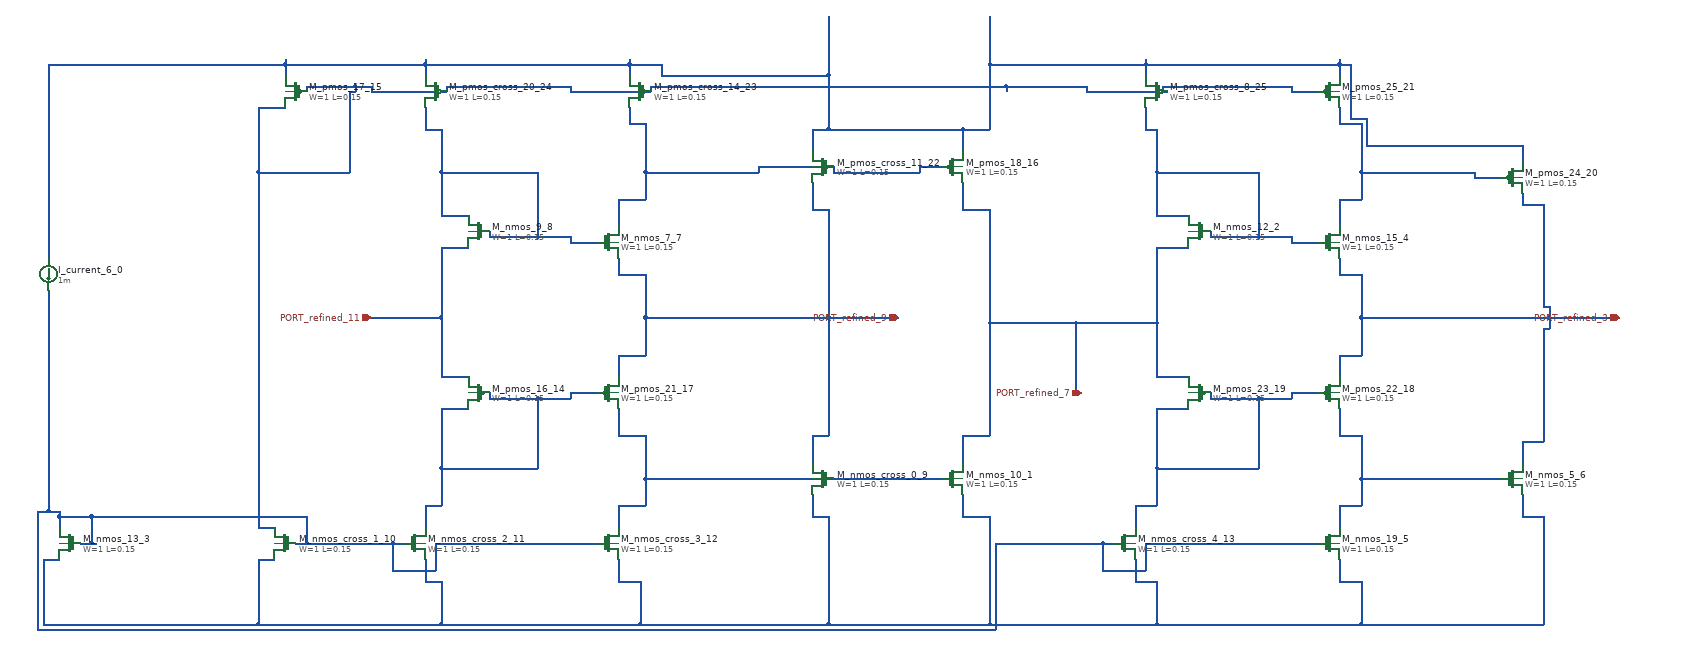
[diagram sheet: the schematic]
v {xschem version=3.4.8 file_version=1.2}
G {}
K {}
V {}
S {}
E {}
C {devices/isource.sym} 120 500 0 0 {name="I_current_6_0" value=1m}
C {sky130_fd_pr/nfet3_01v8.sym} 1800 880 0 0 {name="M_nmos_10_1"
W=1
L=0.15
body=GND
nf=1
mult=1
ad="expr('int((@nf + 1)/2) * @W / @nf * 0.29')"
pd="expr('2*int((@nf + 1)/2) * (@W / @nf + 0.29)')"
as="expr('int((@nf + 2)/2) * @W / @nf * 0.29')"
ps="expr('2*int((@nf + 2)/2) * (@W / @nf + 0.29)')"
nrd="expr('0.29 / @W ')" nrs="expr('0.29 / @W ')"
sa=0 sb=0 sd=0
model=nfet_01v8
spiceprefix=X
}
C {sky130_fd_pr/nfet3_01v8.sym} 2260 420 0 1 {name="M_nmos_12_2"
W=1
L=0.15
body=GND
nf=1
mult=1
ad="expr('int((@nf + 1)/2) * @W / @nf * 0.29')"
pd="expr('2*int((@nf + 1)/2) * (@W / @nf + 0.29)')"
as="expr('int((@nf + 2)/2) * @W / @nf * 0.29')"
ps="expr('2*int((@nf + 2)/2) * (@W / @nf + 0.29)')"
nrd="expr('0.29 / @W ')" nrs="expr('0.29 / @W ')"
sa=0 sb=0 sd=0
model=nfet_01v8
spiceprefix=X
}
C {sky130_fd_pr/nfet3_01v8.sym} 160 1000 0 1 {name="M_nmos_13_3"
W=1
L=0.15
body=GND
nf=1
mult=1
ad="expr('int((@nf + 1)/2) * @W / @nf * 0.29')"
pd="expr('2*int((@nf + 1)/2) * (@W / @nf + 0.29)')"
as="expr('int((@nf + 2)/2) * @W / @nf * 0.29')"
ps="expr('2*int((@nf + 2)/2) * (@W / @nf + 0.29)')"
nrd="expr('0.29 / @W ')" nrs="expr('0.29 / @W ')"
sa=0 sb=0 sd=0
model=nfet_01v8
spiceprefix=X
}
C {sky130_fd_pr/nfet3_01v8.sym} 2500 440 0 0 {name="M_nmos_15_4"
W=1
L=0.15
body=GND
nf=1
mult=1
ad="expr('int((@nf + 1)/2) * @W / @nf * 0.29')"
pd="expr('2*int((@nf + 1)/2) * (@W / @nf + 0.29)')"
as="expr('int((@nf + 2)/2) * @W / @nf * 0.29')"
ps="expr('2*int((@nf + 2)/2) * (@W / @nf + 0.29)')"
nrd="expr('0.29 / @W ')" nrs="expr('0.29 / @W ')"
sa=0 sb=0 sd=0
model=nfet_01v8
spiceprefix=X
}
C {sky130_fd_pr/nfet3_01v8.sym} 2500 1000 0 0 {name="M_nmos_19_5"
W=1
L=0.15
body=GND
nf=1
mult=1
ad="expr('int((@nf + 1)/2) * @W / @nf * 0.29')"
pd="expr('2*int((@nf + 1)/2) * (@W / @nf + 0.29)')"
as="expr('int((@nf + 2)/2) * @W / @nf * 0.29')"
ps="expr('2*int((@nf + 2)/2) * (@W / @nf + 0.29)')"
nrd="expr('0.29 / @W ')" nrs="expr('0.29 / @W ')"
sa=0 sb=0 sd=0
model=nfet_01v8
spiceprefix=X
}
C {sky130_fd_pr/nfet3_01v8.sym} 2840 880 0 0 {name="M_nmos_5_6"
W=1
L=0.15
body=GND
nf=1
mult=1
ad="expr('int((@nf + 1)/2) * @W / @nf * 0.29')"
pd="expr('2*int((@nf + 1)/2) * (@W / @nf + 0.29)')"
as="expr('int((@nf + 2)/2) * @W / @nf * 0.29')"
ps="expr('2*int((@nf + 2)/2) * (@W / @nf + 0.29)')"
nrd="expr('0.29 / @W ')" nrs="expr('0.29 / @W ')"
sa=0 sb=0 sd=0
model=nfet_01v8
spiceprefix=X
}
C {sky130_fd_pr/nfet3_01v8.sym} 1160 440 0 0 {name="M_nmos_7_7"
W=1
L=0.15
body=GND
nf=1
mult=1
ad="expr('int((@nf + 1)/2) * @W / @nf * 0.29')"
pd="expr('2*int((@nf + 1)/2) * (@W / @nf + 0.29)')"
as="expr('int((@nf + 2)/2) * @W / @nf * 0.29')"
ps="expr('2*int((@nf + 2)/2) * (@W / @nf + 0.29)')"
nrd="expr('0.29 / @W ')" nrs="expr('0.29 / @W ')"
sa=0 sb=0 sd=0
model=nfet_01v8
spiceprefix=X
}
C {sky130_fd_pr/nfet3_01v8.sym} 920 420 0 1 {name="M_nmos_9_8"
W=1
L=0.15
body=GND
nf=1
mult=1
ad="expr('int((@nf + 1)/2) * @W / @nf * 0.29')"
pd="expr('2*int((@nf + 1)/2) * (@W / @nf + 0.29)')"
as="expr('int((@nf + 2)/2) * @W / @nf * 0.29')"
ps="expr('2*int((@nf + 2)/2) * (@W / @nf + 0.29)')"
nrd="expr('0.29 / @W ')" nrs="expr('0.29 / @W ')"
sa=0 sb=0 sd=0
model=nfet_01v8
spiceprefix=X
}
C {sky130_fd_pr/nfet3_01v8.sym} 1560 880 0 1 {name="M_nmos_cross_0_9"
W=1
L=0.15
body=GND
nf=1
mult=1
ad="expr('int((@nf + 1)/2) * @W / @nf * 0.29')"
pd="expr('2*int((@nf + 1)/2) * (@W / @nf + 0.29)')"
as="expr('int((@nf + 2)/2) * @W / @nf * 0.29')"
ps="expr('2*int((@nf + 2)/2) * (@W / @nf + 0.29)')"
nrd="expr('0.29 / @W ')" nrs="expr('0.29 / @W ')"
sa=0 sb=0 sd=0
model=nfet_01v8
spiceprefix=X
}
C {sky130_fd_pr/nfet3_01v8.sym} 560 1000 0 1 {name="M_nmos_cross_1_10"
W=1
L=0.15
body=GND
nf=1
mult=1
ad="expr('int((@nf + 1)/2) * @W / @nf * 0.29')"
pd="expr('2*int((@nf + 1)/2) * (@W / @nf + 0.29)')"
as="expr('int((@nf + 2)/2) * @W / @nf * 0.29')"
ps="expr('2*int((@nf + 2)/2) * (@W / @nf + 0.29)')"
nrd="expr('0.29 / @W ')" nrs="expr('0.29 / @W ')"
sa=0 sb=0 sd=0
model=nfet_01v8
spiceprefix=X
}
C {sky130_fd_pr/nfet3_01v8.sym} 800 1000 0 0 {name="M_nmos_cross_2_11"
W=1
L=0.15
body=GND
nf=1
mult=1
ad="expr('int((@nf + 1)/2) * @W / @nf * 0.29')"
pd="expr('2*int((@nf + 1)/2) * (@W / @nf + 0.29)')"
as="expr('int((@nf + 2)/2) * @W / @nf * 0.29')"
ps="expr('2*int((@nf + 2)/2) * (@W / @nf + 0.29)')"
nrd="expr('0.29 / @W ')" nrs="expr('0.29 / @W ')"
sa=0 sb=0 sd=0
model=nfet_01v8
spiceprefix=X
}
C {sky130_fd_pr/nfet3_01v8.sym} 1160 1000 0 0 {name="M_nmos_cross_3_12"
W=1
L=0.15
body=GND
nf=1
mult=1
ad="expr('int((@nf + 1)/2) * @W / @nf * 0.29')"
pd="expr('2*int((@nf + 1)/2) * (@W / @nf + 0.29)')"
as="expr('int((@nf + 2)/2) * @W / @nf * 0.29')"
ps="expr('2*int((@nf + 2)/2) * (@W / @nf + 0.29)')"
nrd="expr('0.29 / @W ')" nrs="expr('0.29 / @W ')"
sa=0 sb=0 sd=0
model=nfet_01v8
spiceprefix=X
}
C {sky130_fd_pr/nfet3_01v8.sym} 2120 1000 0 0 {name="M_nmos_cross_4_13"
W=1
L=0.15
body=GND
nf=1
mult=1
ad="expr('int((@nf + 1)/2) * @W / @nf * 0.29')"
pd="expr('2*int((@nf + 1)/2) * (@W / @nf + 0.29)')"
as="expr('int((@nf + 2)/2) * @W / @nf * 0.29')"
ps="expr('2*int((@nf + 2)/2) * (@W / @nf + 0.29)')"
nrd="expr('0.29 / @W ')" nrs="expr('0.29 / @W ')"
sa=0 sb=0 sd=0
model=nfet_01v8
spiceprefix=X
}
C {sky130_fd_pr/pfet3_01v8.sym} 920 720 0 1 {name="M_pmos_16_14"
W=1
L=0.15
body=VDD
nf=1
mult=1
ad="expr('int((@nf + 1)/2) * @W / @nf * 0.29')"
pd="expr('2*int((@nf + 1)/2) * (@W / @nf + 0.29)')"
as="expr('int((@nf + 2)/2) * @W / @nf * 0.29')"
ps="expr('2*int((@nf + 2)/2) * (@W / @nf + 0.29)')"
nrd="expr('0.29 / @W ')" nrs="expr('0.29 / @W ')"
sa=0 sb=0 sd=0
model=pfet_01v8
spiceprefix=X
}
C {sky130_fd_pr/pfet3_01v8.sym} 580 160 0 1 {name="M_pmos_17_15"
W=1
L=0.15
body=VDD
nf=1
mult=1
ad="expr('int((@nf + 1)/2) * @W / @nf * 0.29')"
pd="expr('2*int((@nf + 1)/2) * (@W / @nf + 0.29)')"
as="expr('int((@nf + 2)/2) * @W / @nf * 0.29')"
ps="expr('2*int((@nf + 2)/2) * (@W / @nf + 0.29)')"
nrd="expr('0.29 / @W ')" nrs="expr('0.29 / @W ')"
sa=0 sb=0 sd=0
model=pfet_01v8
spiceprefix=X
}
C {sky130_fd_pr/pfet3_01v8.sym} 1800 300 0 0 {name="M_pmos_18_16"
W=1
L=0.15
body=VDD
nf=1
mult=1
ad="expr('int((@nf + 1)/2) * @W / @nf * 0.29')"
pd="expr('2*int((@nf + 1)/2) * (@W / @nf + 0.29)')"
as="expr('int((@nf + 2)/2) * @W / @nf * 0.29')"
ps="expr('2*int((@nf + 2)/2) * (@W / @nf + 0.29)')"
nrd="expr('0.29 / @W ')" nrs="expr('0.29 / @W ')"
sa=0 sb=0 sd=0
model=pfet_01v8
spiceprefix=X
}
C {sky130_fd_pr/pfet3_01v8.sym} 1160 720 0 0 {name="M_pmos_21_17"
W=1
L=0.15
body=VDD
nf=1
mult=1
ad="expr('int((@nf + 1)/2) * @W / @nf * 0.29')"
pd="expr('2*int((@nf + 1)/2) * (@W / @nf + 0.29)')"
as="expr('int((@nf + 2)/2) * @W / @nf * 0.29')"
ps="expr('2*int((@nf + 2)/2) * (@W / @nf + 0.29)')"
nrd="expr('0.29 / @W ')" nrs="expr('0.29 / @W ')"
sa=0 sb=0 sd=0
model=pfet_01v8
spiceprefix=X
}
C {sky130_fd_pr/pfet3_01v8.sym} 2500 720 0 0 {name="M_pmos_22_18"
W=1
L=0.15
body=VDD
nf=1
mult=1
ad="expr('int((@nf + 1)/2) * @W / @nf * 0.29')"
pd="expr('2*int((@nf + 1)/2) * (@W / @nf + 0.29)')"
as="expr('int((@nf + 2)/2) * @W / @nf * 0.29')"
ps="expr('2*int((@nf + 2)/2) * (@W / @nf + 0.29)')"
nrd="expr('0.29 / @W ')" nrs="expr('0.29 / @W ')"
sa=0 sb=0 sd=0
model=pfet_01v8
spiceprefix=X
}
C {sky130_fd_pr/pfet3_01v8.sym} 2260 720 0 1 {name="M_pmos_23_19"
W=1
L=0.15
body=VDD
nf=1
mult=1
ad="expr('int((@nf + 1)/2) * @W / @nf * 0.29')"
pd="expr('2*int((@nf + 1)/2) * (@W / @nf + 0.29)')"
as="expr('int((@nf + 2)/2) * @W / @nf * 0.29')"
ps="expr('2*int((@nf + 2)/2) * (@W / @nf + 0.29)')"
nrd="expr('0.29 / @W ')" nrs="expr('0.29 / @W ')"
sa=0 sb=0 sd=0
model=pfet_01v8
spiceprefix=X
}
C {sky130_fd_pr/pfet3_01v8.sym} 2840 320 0 0 {name="M_pmos_24_20"
W=1
L=0.15
body=VDD
nf=1
mult=1
ad="expr('int((@nf + 1)/2) * @W / @nf * 0.29')"
pd="expr('2*int((@nf + 1)/2) * (@W / @nf + 0.29)')"
as="expr('int((@nf + 2)/2) * @W / @nf * 0.29')"
ps="expr('2*int((@nf + 2)/2) * (@W / @nf + 0.29)')"
nrd="expr('0.29 / @W ')" nrs="expr('0.29 / @W ')"
sa=0 sb=0 sd=0
model=pfet_01v8
spiceprefix=X
}
C {sky130_fd_pr/pfet3_01v8.sym} 2500 160 0 0 {name="M_pmos_25_21"
W=1
L=0.15
body=VDD
nf=1
mult=1
ad="expr('int((@nf + 1)/2) * @W / @nf * 0.29')"
pd="expr('2*int((@nf + 1)/2) * (@W / @nf + 0.29)')"
as="expr('int((@nf + 2)/2) * @W / @nf * 0.29')"
ps="expr('2*int((@nf + 2)/2) * (@W / @nf + 0.29)')"
nrd="expr('0.29 / @W ')" nrs="expr('0.29 / @W ')"
sa=0 sb=0 sd=0
model=pfet_01v8
spiceprefix=X
}
C {sky130_fd_pr/pfet3_01v8.sym} 1560 300 0 1 {name="M_pmos_cross_11_22"
W=1
L=0.15
body=VDD
nf=1
mult=1
ad="expr('int((@nf + 1)/2) * @W / @nf * 0.29')"
pd="expr('2*int((@nf + 1)/2) * (@W / @nf + 0.29)')"
as="expr('int((@nf + 2)/2) * @W / @nf * 0.29')"
ps="expr('2*int((@nf + 2)/2) * (@W / @nf + 0.29)')"
nrd="expr('0.29 / @W ')" nrs="expr('0.29 / @W ')"
sa=0 sb=0 sd=0
model=pfet_01v8
spiceprefix=X
}
C {sky130_fd_pr/pfet3_01v8.sym} 1220 160 0 1 {name="M_pmos_cross_14_23"
W=1
L=0.15
body=VDD
nf=1
mult=1
ad="expr('int((@nf + 1)/2) * @W / @nf * 0.29')"
pd="expr('2*int((@nf + 1)/2) * (@W / @nf + 0.29)')"
as="expr('int((@nf + 2)/2) * @W / @nf * 0.29')"
ps="expr('2*int((@nf + 2)/2) * (@W / @nf + 0.29)')"
nrd="expr('0.29 / @W ')" nrs="expr('0.29 / @W ')"
sa=0 sb=0 sd=0
model=pfet_01v8
spiceprefix=X
}
C {sky130_fd_pr/pfet3_01v8.sym} 840 160 0 1 {name="M_pmos_cross_20_24"
W=1
L=0.15
body=VDD
nf=1
mult=1
ad="expr('int((@nf + 1)/2) * @W / @nf * 0.29')"
pd="expr('2*int((@nf + 1)/2) * (@W / @nf + 0.29)')"
as="expr('int((@nf + 2)/2) * @W / @nf * 0.29')"
ps="expr('2*int((@nf + 2)/2) * (@W / @nf + 0.29)')"
nrd="expr('0.29 / @W ')" nrs="expr('0.29 / @W ')"
sa=0 sb=0 sd=0
model=pfet_01v8
spiceprefix=X
}
C {sky130_fd_pr/pfet3_01v8.sym} 2180 160 0 1 {name="M_pmos_cross_8_25"
W=1
L=0.15
body=VDD
nf=1
mult=1
ad="expr('int((@nf + 1)/2) * @W / @nf * 0.29')"
pd="expr('2*int((@nf + 1)/2) * (@W / @nf + 0.29)')"
as="expr('int((@nf + 2)/2) * @W / @nf * 0.29')"
ps="expr('2*int((@nf + 2)/2) * (@W / @nf + 0.29)')"
nrd="expr('0.29 / @W ')" nrs="expr('0.29 / @W ')"
sa=0 sb=0 sd=0
model=pfet_01v8
spiceprefix=X
}
C {devices/ipin.sym} 3040 580 0 0 {name="p_port_27_26" lab="PORT_refined_3"}
C {devices/ipin.sym} 720 580 0 0 {name="p_port_31_27" lab="PORT_refined_11"}
C {devices/ipin.sym} 1700 580 0 0 {name="p_port_32_28" lab="PORT_refined_9"}
C {devices/ipin.sym} 2040 720 0 0 {name="p_port_33_29" lab="PORT_refined_7"}
N 100 1160 1880 1160 {}
N 760 1050 840 1050 {}
N 2080 1050 2160 1050 {}
N 180 1000 200 1000 {}
N 200 1000 210 1000 {}
N 580 1000 600 1000 {}
N 600 1000 760 1000 {}
N 760 1000 780 1000 {}
N 840 1000 1140 1000 {}
N 1880 1000 2080 1000 {}
N 2080 1000 2100 1000 {}
N 2160 1000 2480 1000 {}
N 140 950 200 950 {}
N 200 950 600 950 {}
N 100 940 120 940 {}
N 120 940 140 940 {}
N 100 1160 100 940 {}
N 120 940 120 530 {}
N 140 970 140 950 {}
N 140 950 140 940 {}
N 200 1000 200 950 {}
N 600 1000 600 950 {}
N 760 1050 760 1000 {}
N 840 1050 840 1000 {}
N 1880 1160 1880 1000 {}
N 2080 1050 2080 1000 {}
N 2160 1050 2160 1000 {}
N 2570 260 2860 260 {}
N 1540 230 1570 230 {}
N 1570 230 1820 230 {}
N 1820 230 1870 230 {}
N 2540 210 2570 210 {}
N 1260 130 1570 130 {}
N 120 110 560 110 {}
N 560 110 820 110 {}
N 820 110 1200 110 {}
N 1200 110 1260 110 {}
N 1870 110 2160 110 {}
N 2160 110 2520 110 {}
N 2520 110 2540 110 {}
N 120 470 120 110 {}
N 560 130 560 110 {}
N 560 110 560 100 {}
N 820 130 820 110 {}
N 820 110 820 100 {}
N 1200 130 1200 110 {}
N 1200 110 1200 100 {}
N 1260 130 1260 110 {}
N 1540 270 1540 230 {}
N 1570 230 1570 130 {}
N 1570 130 1570 20 {}
N 1820 270 1820 230 {}
N 1870 230 1870 110 {}
N 1870 110 1870 20 {}
N 2160 130 2160 110 {}
N 2160 110 2160 100 {}
N 2520 130 2520 110 {}
N 2520 110 2520 100 {}
N 2540 210 2540 110 {}
N 2570 260 2570 210 {}
N 2860 290 2860 260 {}
N 1090 440 1140 440 {}
N 940 430 1030 430 {}
N 1030 430 1090 430 {}
N 850 390 900 390 {}
N 850 310 1030 310 {}
N 820 230 850 230 {}
N 820 230 820 190 {}
N 850 390 850 310 {}
N 850 310 850 230 {}
N 940 430 940 420 {}
N 1030 430 1030 310 {}
N 1090 440 1090 430 {}
N 850 690 900 690 {}
N 720 580 850 580 {}
N 850 450 900 450 {}
N 850 690 850 580 {}
N 850 580 850 450 {}
N 1180 930 1230 930 {}
N 1230 880 1580 880 {}
N 1580 880 1780 880 {}
N 1180 800 1230 800 {}
N 1180 970 1180 930 {}
N 1180 800 1180 750 {}
N 1230 930 1230 880 {}
N 1230 880 1230 800 {}
N 510 970 540 970 {}
N 510 310 680 310 {}
N 510 190 560 190 {}
N 680 160 690 160 {}
N 720 160 860 160 {}
N 1090 160 1240 160 {}
N 2050 160 2190 160 {}
N 2190 160 2200 160 {}
N 2430 160 2480 160 {}
N 600 150 690 150 {}
N 690 150 720 150 {}
N 860 150 1090 150 {}
N 1240 150 1900 150 {}
N 1900 150 2050 150 {}
N 2190 150 2430 150 {}
N 510 970 510 310 {}
N 510 310 510 190 {}
N 600 160 600 150 {}
N 680 310 680 160 {}
N 690 160 690 150 {}
N 720 160 720 150 {}
N 860 160 860 150 {}
N 1090 160 1090 150 {}
N 1240 160 1240 150 {}
N 1900 160 1900 150 {}
N 2050 160 2050 150 {}
N 2190 160 2190 150 {}
N 2430 160 2430 150 {}
N 820 930 850 930 {}
N 850 860 1030 860 {}
N 850 750 900 750 {}
N 940 730 1030 730 {}
N 1030 730 1090 730 {}
N 1090 720 1140 720 {}
N 820 970 820 930 {}
N 850 930 850 860 {}
N 850 860 850 750 {}
N 940 730 940 720 {}
N 1030 860 1030 730 {}
N 1090 730 1090 720 {}
N 2140 930 2180 930 {}
N 2180 860 2370 860 {}
N 2180 750 2240 750 {}
N 2280 730 2370 730 {}
N 2370 730 2430 730 {}
N 2430 720 2480 720 {}
N 2140 970 2140 930 {}
N 2180 930 2180 860 {}
N 2180 860 2180 750 {}
N 2280 730 2280 720 {}
N 2370 860 2370 730 {}
N 2430 730 2430 720 {}
N 2520 360 2560 360 {}
N 2770 320 2820 320 {}
N 2560 310 2770 310 {}
N 2520 220 2560 220 {}
N 2520 410 2520 360 {}
N 2520 220 2520 190 {}
N 2560 360 2560 310 {}
N 2560 310 2560 220 {}
N 2770 320 2770 310 {}
N 2860 810 2900 810 {}
N 2520 650 2560 650 {}
N 2900 600 2910 600 {}
N 2560 580 2910 580 {}
N 2910 580 3040 580 {}
N 2900 560 2910 560 {}
N 2520 500 2560 500 {}
N 2860 370 2900 370 {}
N 2520 690 2520 650 {}
N 2520 500 2520 470 {}
N 2560 650 2560 580 {}
N 2560 580 2560 500 {}
N 2860 850 2860 810 {}
N 2860 370 2860 350 {}
N 2900 810 2900 600 {}
N 2900 560 2900 370 {}
N 2910 600 2910 580 {}
N 2910 580 2910 560 {}
N 2430 440 2480 440 {}
N 2280 430 2370 430 {}
N 2370 430 2430 430 {}
N 2180 390 2240 390 {}
N 2180 310 2370 310 {}
N 2160 230 2180 230 {}
N 2160 230 2160 190 {}
N 2180 390 2180 310 {}
N 2180 310 2180 230 {}
N 2280 430 2280 420 {}
N 2370 430 2370 310 {}
N 2430 440 2430 430 {}
N 2520 930 2560 930 {}
N 2560 880 2820 880 {}
N 2520 800 2560 800 {}
N 2520 970 2520 930 {}
N 2520 800 2520 750 {}
N 2560 930 2560 880 {}
N 2560 880 2560 800 {}
N 110 1150 510 1150 {}
N 510 1150 850 1150 {}
N 850 1150 1220 1150 {}
N 1220 1150 1570 1150 {}
N 1570 1150 1870 1150 {}
N 1870 1150 2180 1150 {}
N 2180 1150 2560 1150 {}
N 2560 1150 2900 1150 {}
N 820 1070 850 1070 {}
N 1180 1070 1220 1070 {}
N 2140 1070 2180 1070 {}
N 2520 1070 2560 1070 {}
N 110 1030 140 1030 {}
N 510 1030 540 1030 {}
N 1540 950 1570 950 {}
N 1820 950 1870 950 {}
N 2860 950 2900 950 {}
N 110 1150 110 1030 {}
N 510 1150 510 1030 {}
N 820 1070 820 1030 {}
N 850 1150 850 1070 {}
N 1180 1070 1180 1030 {}
N 1220 1150 1220 1070 {}
N 1540 950 1540 910 {}
N 1570 1150 1570 950 {}
N 1820 950 1820 910 {}
N 1870 1150 1870 950 {}
N 2140 1070 2140 1030 {}
N 2180 1150 2180 1070 {}
N 2520 1070 2520 1030 {}
N 2560 1150 2560 1070 {}
N 2860 950 2860 910 {}
N 2900 1150 2900 950 {}
N 1820 800 1870 800 {}
N 2030 720 2040 720 {}
N 2180 690 2240 690 {}
N 1870 590 2030 590 {}
N 2030 590 2180 590 {}
N 2180 450 2240 450 {}
N 1820 380 1870 380 {}
N 1820 850 1820 800 {}
N 1820 380 1820 330 {}
N 1870 800 1870 590 {}
N 1870 590 1870 380 {}
N 2030 720 2030 590 {}
N 2180 690 2180 590 {}
N 2180 590 2180 450 {}
N 1180 360 1230 360 {}
N 1230 310 1440 310 {}
N 1580 310 1740 310 {}
N 1440 300 1580 300 {}
N 1740 300 1780 300 {}
N 1200 220 1230 220 {}
N 1180 410 1180 360 {}
N 1200 220 1200 190 {}
N 1230 360 1230 310 {}
N 1230 310 1230 220 {}
N 1440 310 1440 300 {}
N 1580 310 1580 300 {}
N 1740 310 1740 300 {}
N 1540 800 1570 800 {}
N 1180 650 1230 650 {}
N 1230 580 1570 580 {}
N 1570 580 1700 580 {}
N 1180 500 1230 500 {}
N 1540 380 1570 380 {}
N 1180 690 1180 650 {}
N 1180 500 1180 470 {}
N 1230 650 1230 580 {}
N 1230 580 1230 500 {}
N 1540 850 1540 800 {}
N 1540 380 1540 330 {}
N 1570 800 1570 580 {}
N 1570 580 1570 380 {}
